VERSION 5.7 ;
  NOWIREEXTENSIONATPIN ON ;
  DIVIDERCHAR "/" ;
  BUSBITCHARS "[]" ;
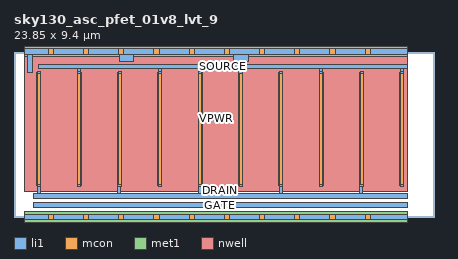
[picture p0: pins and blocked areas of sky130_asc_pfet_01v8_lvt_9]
MACRO sky130_asc_pfet_01v8_lvt_9
  CLASS CORE ;
  FOREIGN sky130_asc_pfet_01v8_lvt_9 ;
  ORIGIN 0.000 0.000 ;
  SIZE 23.850 BY 9.400 ;
  SITE unitasc ;
  PIN GATE
    DIRECTION INOUT ;
    USE SIGNAL ;
    ANTENNAGATEAREA 116.099998 ;
    PORT
      LAYER li1 ;
        RECT 1.090 0.520 22.350 0.820 ;
    END
  END GATE
  PIN SOURCE
    DIRECTION INOUT ;
    USE SIGNAL ;
    ANTENNADIFFAREA 9.352500 ;
    PORT
      LAYER li1 ;
        RECT 1.390 8.450 22.350 8.650 ;
        RECT 3.615 8.245 3.785 8.450 ;
        RECT 8.195 8.245 8.365 8.450 ;
        RECT 12.775 8.245 12.945 8.450 ;
        RECT 17.355 8.245 17.525 8.450 ;
        RECT 21.935 8.245 22.105 8.450 ;
        RECT 3.615 8.130 3.790 8.245 ;
        RECT 8.195 8.130 8.370 8.245 ;
        RECT 12.775 8.130 12.950 8.245 ;
        RECT 17.355 8.130 17.530 8.245 ;
        RECT 21.935 8.130 22.110 8.245 ;
        RECT 3.620 1.755 3.790 8.130 ;
        RECT 8.200 1.755 8.370 8.130 ;
        RECT 12.780 1.755 12.950 8.130 ;
        RECT 17.360 1.755 17.530 8.130 ;
        RECT 21.940 1.755 22.110 8.130 ;
      LAYER mcon ;
        RECT 3.620 1.835 3.790 8.165 ;
        RECT 8.200 1.835 8.370 8.165 ;
        RECT 12.780 1.835 12.950 8.165 ;
        RECT 17.360 1.835 17.530 8.165 ;
        RECT 21.940 1.835 22.110 8.165 ;
      LAYER met1 ;
        RECT 3.590 1.775 3.820 8.225 ;
        RECT 8.170 1.775 8.400 8.225 ;
        RECT 12.750 1.775 12.980 8.225 ;
        RECT 17.330 1.775 17.560 8.225 ;
        RECT 21.910 1.775 22.140 8.225 ;
    END
  END SOURCE
  PIN DRAIN
    DIRECTION INOUT ;
    USE SIGNAL ;
    ANTENNADIFFAREA 9.352500 ;
    PORT
      LAYER li1 ;
        RECT 1.330 1.870 1.500 8.245 ;
        RECT 5.910 1.870 6.080 8.245 ;
        RECT 10.490 1.870 10.660 8.245 ;
        RECT 15.070 1.870 15.240 8.245 ;
        RECT 19.650 1.870 19.820 8.245 ;
        RECT 1.325 1.755 1.500 1.870 ;
        RECT 5.905 1.755 6.080 1.870 ;
        RECT 10.485 1.755 10.660 1.870 ;
        RECT 15.065 1.755 15.240 1.870 ;
        RECT 19.645 1.755 19.820 1.870 ;
        RECT 1.325 1.350 1.495 1.755 ;
        RECT 5.905 1.350 6.075 1.755 ;
        RECT 10.485 1.350 10.655 1.755 ;
        RECT 15.065 1.350 15.235 1.755 ;
        RECT 19.645 1.350 19.815 1.755 ;
        RECT 1.090 1.050 22.350 1.350 ;
      LAYER mcon ;
        RECT 1.330 1.835 1.500 8.165 ;
        RECT 5.910 1.835 6.080 8.165 ;
        RECT 10.490 1.835 10.660 8.165 ;
        RECT 15.070 1.835 15.240 8.165 ;
        RECT 19.650 1.835 19.820 8.165 ;
      LAYER met1 ;
        RECT 1.300 1.775 1.530 8.225 ;
        RECT 5.880 1.775 6.110 8.225 ;
        RECT 10.460 1.775 10.690 8.225 ;
        RECT 15.040 1.775 15.270 8.225 ;
        RECT 19.620 1.775 19.850 8.225 ;
    END
  END DRAIN
  PIN VPWR
    DIRECTION INOUT ;
    USE POWER ;
    PORT
      LAYER nwell ;
        RECT 0.600 1.470 22.350 9.700 ;
        RECT 1.090 1.465 22.350 1.470 ;
      LAYER li1 ;
        RECT 0.600 9.250 22.350 9.550 ;
        RECT 0.740 8.200 1.040 9.250 ;
        RECT 5.990 8.850 6.790 9.250 ;
        RECT 12.490 8.850 13.290 9.250 ;
      LAYER mcon ;
        RECT 1.940 9.250 2.240 9.550 ;
        RECT 3.940 9.250 4.240 9.550 ;
        RECT 5.940 9.250 6.240 9.550 ;
        RECT 7.940 9.250 8.240 9.550 ;
        RECT 9.940 9.250 10.240 9.550 ;
        RECT 11.940 9.250 12.240 9.550 ;
        RECT 13.940 9.250 14.240 9.550 ;
        RECT 15.940 9.250 16.240 9.550 ;
        RECT 17.940 9.250 18.240 9.550 ;
        RECT 19.940 9.250 20.240 9.550 ;
      LAYER met1 ;
        RECT 0.600 9.100 22.350 9.700 ;
    END
  END VPWR
  PIN VGND
    DIRECTION INOUT ;
    USE GROUND ;
    PORT
      LAYER li1 ;
        RECT 0.600 -0.150 22.350 0.150 ;
      LAYER mcon ;
        RECT 1.940 -0.150 2.240 0.150 ;
        RECT 3.940 -0.150 4.240 0.150 ;
        RECT 5.940 -0.150 6.240 0.150 ;
        RECT 7.940 -0.150 8.240 0.150 ;
        RECT 9.940 -0.150 10.240 0.150 ;
        RECT 11.940 -0.150 12.240 0.150 ;
        RECT 13.940 -0.150 14.240 0.150 ;
        RECT 15.940 -0.150 16.240 0.150 ;
        RECT 17.940 -0.150 18.240 0.150 ;
        RECT 19.940 -0.150 20.240 0.150 ;
      LAYER met1 ;
        RECT 0.600 -0.300 22.350 0.300 ;
    END
  END VGND
END sky130_asc_pfet_01v8_lvt_9
END LIBRARY

